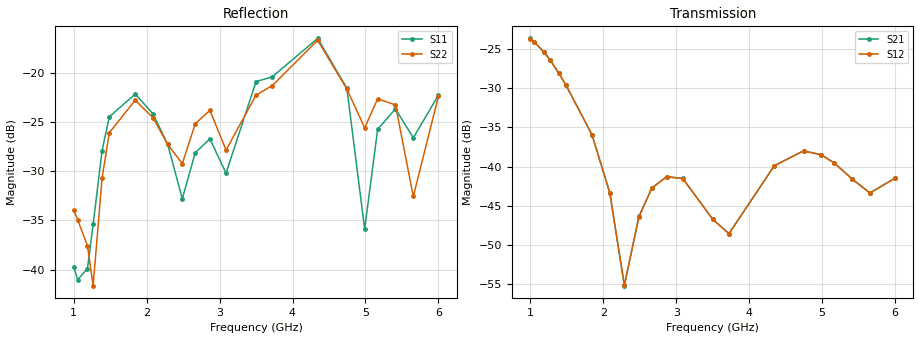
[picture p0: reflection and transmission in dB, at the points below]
!Agilent Technologies,E8364B,MY43040528,A.07.50.67
!Agilent E8364B: A.07.50.67
!Date: Sunday, March 01, 2026 20:41:47
!Correction: S11(Full 2 Port(1,2))
!S21(Full 2 Port(1,2))
!S12(Full 2 Port(1,2))
!S22(Full 2 Port(1,2))
!S2P File: Measurements: S11, S21, S12, S22:
# Hz S  dB  R 50
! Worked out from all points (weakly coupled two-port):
!   451 points, 1 GHz to 6 GHz, reference 50 ohm
!   highest |S21| = -23.63 dB at 1 GHz (marker M1); lowest = -55.2 dB at 2.289 GHz (marker M2)
!   lowest |S11| = -41.0 dB at 1.056 GHz (marker M3), VSWR 1.02, Z = 49.8 + j0.856 ohm
!   |S11| at or under -10 dB: start of sweep to end of sweep
!   |S22| runs from -41.8 to -16.4 dB; largest |S21 - S12| = 0.00017
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1e9  -39.70 77.9  -23.63 148.7  -23.65 148.7  -33.93 21.1
1.055556e9  -41.02 104.7  -24.09 116.5  -24.11 116.5  -34.95 23.8
1.188889e9  -39.89 148.1  -25.40 39.6  -25.42 39.5  -37.57 28.9
1.266667e9  -35.40 177.6  -26.33 -5.2  -26.35 -5.2  -41.63 75.3
1.388889e9  -27.90 174.1  -28.05 -74.4  -28.07 -74.4  -30.69 102.2
1.488889e9  -24.45 155.2  -29.61 -129.6  -29.62 -129.6  -26.07 81.2
1.844444e9  -22.14 92.6  -35.93 37.9  -35.94 37.9  -22.76 3.5
2.088889e9  -24.17 64.3  -43.34 -90.5  -43.37 -90.5  -24.57 -32.7
2.288889e9  -27.26 46.6  -55.22 -135.6  -55.13 -136.0  -27.27 -53.8
2.488889e9  -32.79 65.3  -46.35 -171.7  -46.41 -171.8  -29.22 -44.3
2.666667e9  -28.11 84.5  -42.73 96.5  -42.76 96.4  -25.16 -51.3
2.866667e9  -26.70 59.8  -41.29 -11.2  -41.32 -11.2  -23.80 -89.4
3.088889e9  -30.19 72.8  -41.51 -132.0  -41.54 -132.0  -27.84 -112.6
3.5e9  -20.87 54.6  -46.74 23.3  -46.73 23.2  -22.25 -124.3
3.722222e9  -20.39 35.6  -48.56 -52.6  -48.59 -52.6  -21.29 -146.9
4.344444e9  -16.48 -38.8  -39.89 12.9  -39.91 12.9  -16.68 113.4
4.744444e9  -21.54 -103.5  -37.99 145.9  -38.02 146.0  -21.63 44.0
4.988889e9  -35.88 -77.2  -38.49 1.2  -38.51 1.2  -25.58 47.4
5.166667e9  -25.73 -41.1  -39.54 -106.3  -39.57 -106.3  -22.63 36.4
5.411111e9  -23.65 -78.3  -41.58 98.3  -41.60 98.3  -23.25 -13.8
5.655556e9  -26.59 -80.0  -43.37 -73.3  -43.40 -73.3  -32.55 -14.1
6e9  -22.26 -82.9  -41.47 42.1  -41.49 42.0  -22.38 -15.4
